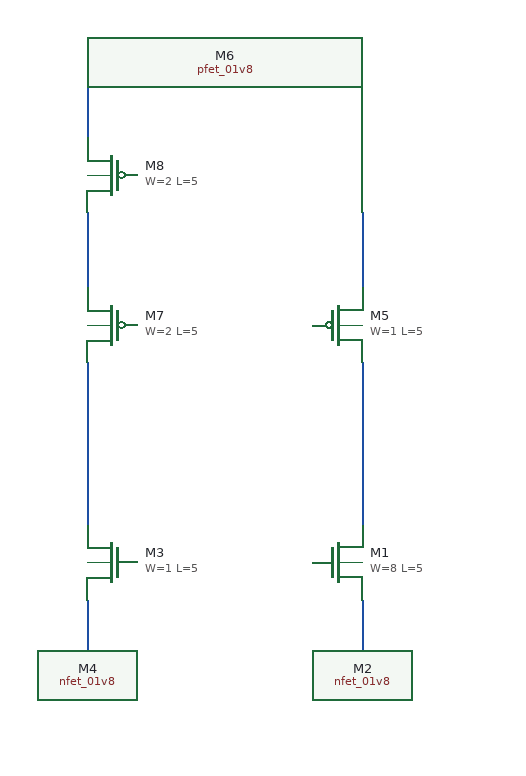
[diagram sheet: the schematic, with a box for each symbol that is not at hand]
v {xschem version=3.0.0 file_version=1.2 }
G {}
K {}
V {}
S {}
E {}
N 190 -160 190 -120 {
lab=#net1}
N 190 -350 190 -220 {
lab=#net2}
N 190 -470 190 -410 {
lab=#net3}
N 190 -570 190 -530 {
lab=#net4}
N 410 -470 410 -410 {
lab=#net5}
N 410 -350 410 -220 {
lab=#net6}
N 410 -160 410 -120 {}
C {sky130_fd_pr/nfet_01v8.sym} 390 -190 0 0 {name=M1
L=5
W=8
nf=1 
mult=1
ad="'int((nf+1)/2) * W/nf * 0.29'" 
pd="'2*int((nf+1)/2) * (W/nf + 0.29)'"
as="'int((nf+2)/2) * W/nf * 0.29'" 
ps="'2*int((nf+2)/2) * (W/nf + 0.29)'"
nrd="'0.29 / W'" nrs="'0.29 / W'"
sa=0 sb=0 sd=0
model=nfet_01v8
spiceprefix=X
}
C {sky130_fd_pr/nfet_01v8.sym} 390 -90 0 0 {name=M2
L=5
W=8
nf=1 
mult=1
ad="'int((nf+1)/2) * W/nf * 0.29'" 
pd="'2*int((nf+1)/2) * (W/nf + 0.29)'"
as="'int((nf+2)/2) * W/nf * 0.29'" 
ps="'2*int((nf+2)/2) * (W/nf + 0.29)'"
nrd="'0.29 / W'" nrs="'0.29 / W'"
sa=0 sb=0 sd=0
model=nfet_01v8
spiceprefix=X
}
C {sky130_fd_pr/nfet_01v8.sym} 210 -190 0 1 {name=M3
L=5
W=1
nf=1 
mult=1
ad="'int((nf+1)/2) * W/nf * 0.29'" 
pd="'2*int((nf+1)/2) * (W/nf + 0.29)'"
as="'int((nf+2)/2) * W/nf * 0.29'" 
ps="'2*int((nf+2)/2) * (W/nf + 0.29)'"
nrd="'0.29 / W'" nrs="'0.29 / W'"
sa=0 sb=0 sd=0
model=nfet_01v8
spiceprefix=X
}
C {sky130_fd_pr/nfet_01v8.sym} 210 -90 0 1 {name=M4
L=5
W=1
nf=1 
mult=1
ad="'int((nf+1)/2) * W/nf * 0.29'" 
pd="'2*int((nf+1)/2) * (W/nf + 0.29)'"
as="'int((nf+2)/2) * W/nf * 0.29'" 
ps="'2*int((nf+2)/2) * (W/nf + 0.29)'"
nrd="'0.29 / W'" nrs="'0.29 / W'"
sa=0 sb=0 sd=0
model=nfet_01v8
spiceprefix=X
}
C {sky130_fd_pr/pfet_01v8.sym} 390 -380 0 0 {name=M5
L=5
W=1
nf=1
mult=1
ad="'int((nf+1)/2) * W/nf * 0.29'" 
pd="'2*int((nf+1)/2) * (W/nf + 0.29)'"
as="'int((nf+2)/2) * W/nf * 0.29'" 
ps="'2*int((nf+2)/2) * (W/nf + 0.29)'"
nrd="'0.29 / W'" nrs="'0.29 / W'"
sa=0 sb=0 sd=0
model=pfet_01v8
spiceprefix=X
}
C {sky130_fd_pr/pfet_01v8.sym} 390 -500 0 0 {name=M6
L=5
W=1
nf=1
mult=1
ad="'int((nf+1)/2) * W/nf * 0.29'" 
pd="'2*int((nf+1)/2) * (W/nf + 0.29)'"
as="'int((nf+2)/2) * W/nf * 0.29'" 
ps="'2*int((nf+2)/2) * (W/nf + 0.29)'"
nrd="'0.29 / W'" nrs="'0.29 / W'"
sa=0 sb=0 sd=0
model=pfet_01v8
spiceprefix=X
}
C {sky130_fd_pr/pfet_01v8.sym} 210 -380 0 1 {name=M7
L=5
W=2
nf=1
mult=1
ad="'int((nf+1)/2) * W/nf * 0.29'" 
pd="'2*int((nf+1)/2) * (W/nf + 0.29)'"
as="'int((nf+2)/2) * W/nf * 0.29'" 
ps="'2*int((nf+2)/2) * (W/nf + 0.29)'"
nrd="'0.29 / W'" nrs="'0.29 / W'"
sa=0 sb=0 sd=0
model=pfet_01v8
spiceprefix=X
}
C {sky130_fd_pr/pfet_01v8.sym} 210 -500 0 1 {name=M8
L=5
W=2
nf=1
mult=1
ad="'int((nf+1)/2) * W/nf * 0.29'" 
pd="'2*int((nf+1)/2) * (W/nf + 0.29)'"
as="'int((nf+2)/2) * W/nf * 0.29'" 
ps="'2*int((nf+2)/2) * (W/nf + 0.29)'"
nrd="'0.29 / W'" nrs="'0.29 / W'"
sa=0 sb=0 sd=0
model=pfet_01v8
spiceprefix=X
}
